VERSION 5.7 ;
  NOWIREEXTENSIONATPIN ON ;
  DIVIDERCHAR "/" ;
  BUSBITCHARS "[]" ;
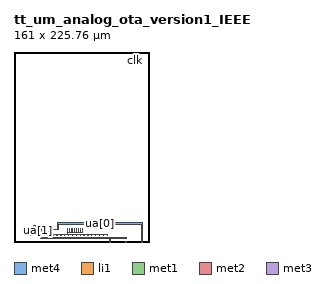
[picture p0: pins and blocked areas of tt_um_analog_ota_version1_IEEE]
MACRO tt_um_analog_ota_version1_IEEE
  CLASS BLOCK ;
  FOREIGN tt_um_analog_ota_version1_IEEE ;
  ORIGIN 0.000 0.000 ;
  SIZE 161.000 BY 225.760 ;
  PIN clk
    PORT
      LAYER met4 ;
        RECT 143.830 224.760 144.130 225.760 ;
    END
  END clk
  PIN ena
    PORT
      LAYER met4 ;
        RECT 146.590 224.760 146.890 225.760 ;
    END
  END ena
  PIN rst_n
    PORT
      LAYER met4 ;
        RECT 141.070 224.760 141.370 225.760 ;
    END
  END rst_n
  PIN ua[0]
    ANTENNAGATEAREA 0.625000 ;
    PORT
      LAYER li1 ;
        RECT 46.745 14.570 47.275 14.740 ;
      LAYER met1 ;
        RECT 49.605 14.800 50.225 14.875 ;
        RECT 46.770 14.510 50.225 14.800 ;
        RECT 49.605 14.395 50.225 14.510 ;
      LAYER met2 ;
        RECT 49.655 14.345 50.175 14.925 ;
      LAYER met3 ;
        RECT 49.605 14.370 50.225 14.900 ;
      LAYER met4 ;
        RECT 149.905 23.100 152.760 23.105 ;
        RECT 51.885 20.845 152.760 23.100 ;
        RECT 51.895 14.895 52.480 20.845 ;
        RECT 151.810 20.790 152.760 20.845 ;
        RECT 50.070 14.880 52.485 14.895 ;
        RECT 49.650 14.390 52.485 14.880 ;
        RECT 50.070 14.365 52.485 14.390 ;
        RECT 151.810 0.320 152.745 20.790 ;
        RECT 151.810 0.000 152.710 0.320 ;
    END
  END ua[0]
  PIN ua[1]
    ANTENNAGATEAREA 0.625000 ;
    ANTENNADIFFAREA 15.500500 ;
    PORT
      LAYER li1 ;
        RECT 45.955 14.570 46.485 14.740 ;
        RECT 63.660 11.000 63.830 16.340 ;
        RECT 66.240 11.000 66.410 16.340 ;
        RECT 68.820 11.000 68.990 16.340 ;
        RECT 71.400 11.000 71.570 16.340 ;
        RECT 73.980 11.000 74.150 16.340 ;
        RECT 76.560 11.000 76.730 16.340 ;
        RECT 79.140 11.000 79.310 16.340 ;
        RECT 81.720 11.000 81.890 16.340 ;
        RECT 20.260 7.885 20.430 8.575 ;
        RECT 41.935 8.270 42.105 8.960 ;
        RECT 46.515 8.270 46.685 8.960 ;
        RECT 51.095 8.270 51.265 8.960 ;
        RECT 55.675 8.270 55.845 8.960 ;
        RECT 60.255 8.270 60.425 8.960 ;
        RECT 64.835 8.270 65.005 8.960 ;
        RECT 69.415 8.270 69.585 8.960 ;
        RECT 73.995 8.270 74.165 8.960 ;
        RECT 78.575 8.270 78.745 8.960 ;
        RECT 83.155 8.270 83.325 8.960 ;
        RECT 87.735 8.270 87.905 8.960 ;
        RECT 92.315 8.270 92.485 8.960 ;
        RECT 96.895 8.270 97.065 8.960 ;
        RECT 101.475 8.270 101.645 8.960 ;
        RECT 106.055 8.270 106.225 8.960 ;
        RECT 110.635 8.270 110.805 8.960 ;
      LAYER met1 ;
        RECT 42.955 14.795 43.595 14.950 ;
        RECT 45.980 14.795 46.460 14.800 ;
        RECT 42.955 14.510 46.460 14.795 ;
        RECT 42.955 14.400 43.595 14.510 ;
        RECT 63.630 11.340 63.860 16.320 ;
        RECT 66.210 11.340 66.440 16.320 ;
        RECT 68.790 11.340 69.020 16.320 ;
        RECT 71.370 11.340 71.600 16.320 ;
        RECT 73.950 11.340 74.180 16.320 ;
        RECT 76.530 11.340 76.760 16.320 ;
        RECT 79.110 11.340 79.340 16.320 ;
        RECT 81.690 11.340 81.920 16.320 ;
        RECT 63.615 11.020 63.875 11.340 ;
        RECT 66.195 11.020 66.455 11.340 ;
        RECT 68.775 11.020 69.035 11.340 ;
        RECT 71.355 11.020 71.615 11.340 ;
        RECT 73.935 11.020 74.195 11.340 ;
        RECT 76.515 11.020 76.775 11.340 ;
        RECT 79.095 11.020 79.355 11.340 ;
        RECT 81.675 11.020 81.935 11.340 ;
        RECT 41.900 8.615 42.160 8.960 ;
        RECT 46.480 8.615 46.740 8.960 ;
        RECT 51.060 8.615 51.320 8.960 ;
        RECT 55.640 8.615 55.900 8.960 ;
        RECT 60.220 8.615 60.480 8.960 ;
        RECT 64.800 8.615 65.060 8.960 ;
        RECT 69.380 8.615 69.640 8.960 ;
        RECT 73.960 8.615 74.220 8.960 ;
        RECT 78.540 8.615 78.800 8.960 ;
        RECT 83.120 8.615 83.380 8.960 ;
        RECT 87.700 8.615 87.960 8.960 ;
        RECT 92.280 8.615 92.540 8.960 ;
        RECT 96.860 8.615 97.120 8.960 ;
        RECT 101.440 8.615 101.700 8.960 ;
        RECT 106.020 8.615 106.280 8.960 ;
        RECT 110.600 8.615 110.860 8.960 ;
        RECT 20.260 8.555 20.430 8.575 ;
        RECT 20.225 8.510 20.460 8.555 ;
        RECT 20.170 8.245 20.535 8.510 ;
        RECT 41.905 8.290 42.135 8.615 ;
        RECT 46.485 8.290 46.715 8.615 ;
        RECT 51.065 8.290 51.295 8.615 ;
        RECT 55.645 8.290 55.875 8.615 ;
        RECT 60.225 8.290 60.455 8.615 ;
        RECT 64.805 8.290 65.035 8.615 ;
        RECT 69.385 8.290 69.615 8.615 ;
        RECT 73.965 8.290 74.195 8.615 ;
        RECT 78.545 8.290 78.775 8.615 ;
        RECT 83.125 8.290 83.355 8.615 ;
        RECT 87.705 8.290 87.935 8.615 ;
        RECT 92.285 8.290 92.515 8.615 ;
        RECT 96.865 8.290 97.095 8.615 ;
        RECT 101.445 8.290 101.675 8.615 ;
        RECT 106.025 8.290 106.255 8.615 ;
        RECT 110.605 8.290 110.835 8.615 ;
        RECT 20.225 7.905 20.460 8.245 ;
      LAYER met2 ;
        RECT 43.005 14.350 43.545 15.000 ;
        RECT 38.480 12.890 42.165 12.900 ;
        RECT 38.215 12.510 42.165 12.890 ;
        RECT 38.480 12.500 42.165 12.510 ;
        RECT 41.895 11.790 42.165 12.500 ;
        RECT 41.900 8.930 42.165 11.790 ;
        RECT 63.585 11.265 63.905 11.310 ;
        RECT 66.165 11.265 66.485 11.310 ;
        RECT 68.745 11.265 69.065 11.310 ;
        RECT 71.325 11.265 71.645 11.310 ;
        RECT 73.905 11.265 74.225 11.310 ;
        RECT 76.485 11.265 76.805 11.310 ;
        RECT 79.065 11.265 79.385 11.310 ;
        RECT 81.645 11.265 81.965 11.310 ;
        RECT 63.585 11.065 81.965 11.265 ;
        RECT 63.585 11.050 63.905 11.065 ;
        RECT 66.165 11.050 66.485 11.065 ;
        RECT 68.745 11.050 69.065 11.065 ;
        RECT 71.325 11.050 71.645 11.065 ;
        RECT 73.905 11.050 74.225 11.065 ;
        RECT 76.485 11.050 76.805 11.065 ;
        RECT 79.065 11.050 79.385 11.065 ;
        RECT 81.645 11.050 81.965 11.065 ;
        RECT 41.850 8.885 42.210 8.930 ;
        RECT 46.430 8.885 46.790 8.930 ;
        RECT 51.010 8.885 51.370 8.930 ;
        RECT 55.590 8.885 55.950 8.930 ;
        RECT 60.170 8.885 60.530 8.930 ;
        RECT 63.615 8.885 63.875 11.050 ;
        RECT 64.750 8.885 65.110 8.930 ;
        RECT 69.330 8.885 69.690 8.930 ;
        RECT 73.910 8.885 74.270 8.930 ;
        RECT 78.490 8.885 78.850 8.930 ;
        RECT 83.070 8.885 83.430 8.930 ;
        RECT 87.650 8.885 88.010 8.930 ;
        RECT 92.230 8.885 92.590 8.930 ;
        RECT 96.810 8.885 97.170 8.930 ;
        RECT 101.390 8.885 101.750 8.930 ;
        RECT 105.970 8.885 106.330 8.930 ;
        RECT 110.550 8.885 110.910 8.930 ;
        RECT 41.850 8.735 110.910 8.885 ;
        RECT 41.850 8.665 42.210 8.735 ;
        RECT 46.430 8.665 46.790 8.735 ;
        RECT 51.010 8.665 51.370 8.735 ;
        RECT 55.590 8.665 55.950 8.735 ;
        RECT 60.170 8.665 60.530 8.735 ;
        RECT 64.750 8.665 65.110 8.735 ;
        RECT 69.330 8.665 69.690 8.735 ;
        RECT 73.910 8.665 74.270 8.735 ;
        RECT 78.490 8.665 78.850 8.735 ;
        RECT 83.070 8.665 83.430 8.735 ;
        RECT 87.650 8.665 88.010 8.735 ;
        RECT 92.230 8.665 92.590 8.735 ;
        RECT 96.810 8.665 97.170 8.735 ;
        RECT 101.390 8.665 101.750 8.735 ;
        RECT 105.970 8.665 106.330 8.735 ;
        RECT 110.550 8.665 110.910 8.735 ;
        RECT 20.205 8.185 20.490 8.560 ;
      LAYER met3 ;
        RECT 22.650 8.900 35.360 19.350 ;
        RECT 42.955 14.375 43.595 14.975 ;
        RECT 38.100 12.450 38.700 12.950 ;
        RECT 21.230 8.550 35.360 8.900 ;
        RECT 20.175 8.530 20.515 8.540 ;
        RECT 21.230 8.530 21.600 8.550 ;
        RECT 20.070 8.230 21.600 8.530 ;
        RECT 22.650 8.400 35.360 8.550 ;
        RECT 20.175 8.205 20.515 8.230 ;
        RECT 21.230 8.225 21.600 8.230 ;
      LAYER met4 ;
        RECT 23.045 12.865 33.205 18.955 ;
        RECT 34.860 12.865 35.340 19.290 ;
        RECT 43.000 14.585 43.550 14.955 ;
        RECT 23.045 12.535 38.565 12.865 ;
        RECT 23.045 12.525 38.260 12.535 ;
        RECT 23.045 8.795 33.205 12.525 ;
        RECT 31.145 5.350 32.650 8.795 ;
        RECT 34.860 8.460 35.340 12.525 ;
        RECT 42.955 5.400 43.620 14.585 ;
        RECT 42.955 5.350 133.425 5.400 ;
        RECT 31.145 4.150 133.425 5.350 ;
        RECT 31.145 4.125 45.100 4.150 ;
<<<<<<< HEAD
        RECT 93.850 0.000 94.750 4.150 ;
        RECT 113.170 0.000 114.070 4.150 ;
=======
>>>>>>> 167fef3d94abc1b400a22c40856cbbf2e635c482
        RECT 132.470 0.715 133.405 4.150 ;
        RECT 132.490 0.000 133.390 0.715 ;
    END
  END ua[1]
<<<<<<< HEAD
=======
  PIN ua[2]
    PORT
      LAYER met4 ;
        RECT 113.170 0.000 114.070 1.000 ;
    END
  END ua[2]
  PIN ua[3]
    PORT
      LAYER met4 ;
        RECT 93.850 0.000 94.750 1.000 ;
    END
  END ua[3]
>>>>>>> 167fef3d94abc1b400a22c40856cbbf2e635c482
  PIN ua[4]
    PORT
      LAYER met4 ;
        RECT 74.530 0.000 75.430 1.000 ;
    END
  END ua[4]
  PIN ua[5]
    PORT
      LAYER met4 ;
        RECT 55.210 0.000 56.110 1.000 ;
    END
  END ua[5]
  PIN ua[6]
    PORT
      LAYER met4 ;
        RECT 35.890 0.000 36.790 1.000 ;
    END
  END ua[6]
  PIN ua[7]
    PORT
      LAYER met4 ;
        RECT 16.570 0.000 17.470 1.000 ;
    END
  END ua[7]
  PIN ui_in[0]
    PORT
      LAYER met4 ;
        RECT 138.310 224.760 138.610 225.760 ;
    END
  END ui_in[0]
  PIN ui_in[1]
    PORT
      LAYER met4 ;
        RECT 135.550 224.760 135.850 225.760 ;
    END
  END ui_in[1]
  PIN ui_in[2]
    PORT
      LAYER met4 ;
        RECT 132.790 224.760 133.090 225.760 ;
    END
  END ui_in[2]
  PIN ui_in[3]
    PORT
      LAYER met4 ;
        RECT 130.030 224.760 130.330 225.760 ;
    END
  END ui_in[3]
  PIN ui_in[4]
    PORT
      LAYER met4 ;
        RECT 127.270 224.760 127.570 225.760 ;
    END
  END ui_in[4]
  PIN ui_in[5]
    PORT
      LAYER met4 ;
        RECT 124.510 224.760 124.810 225.760 ;
    END
  END ui_in[5]
  PIN ui_in[6]
    PORT
      LAYER met4 ;
        RECT 121.750 224.760 122.050 225.760 ;
    END
  END ui_in[6]
  PIN ui_in[7]
    PORT
      LAYER met4 ;
        RECT 118.990 224.760 119.290 225.760 ;
    END
  END ui_in[7]
  PIN uio_in[0]
    PORT
      LAYER met4 ;
        RECT 116.230 224.760 116.530 225.760 ;
    END
  END uio_in[0]
  PIN uio_in[1]
    PORT
      LAYER met4 ;
        RECT 113.470 224.760 113.770 225.760 ;
    END
  END uio_in[1]
  PIN uio_in[2]
    PORT
      LAYER met4 ;
        RECT 110.710 224.760 111.010 225.760 ;
    END
  END uio_in[2]
  PIN uio_in[3]
    PORT
      LAYER met4 ;
        RECT 107.950 224.760 108.250 225.760 ;
    END
  END uio_in[3]
  PIN uio_in[4]
    PORT
      LAYER met4 ;
        RECT 105.190 224.760 105.490 225.760 ;
    END
  END uio_in[4]
  PIN uio_in[5]
    PORT
      LAYER met4 ;
        RECT 102.430 224.760 102.730 225.760 ;
    END
  END uio_in[5]
  PIN uio_in[6]
    PORT
      LAYER met4 ;
        RECT 99.670 224.760 99.970 225.760 ;
    END
  END uio_in[6]
  PIN uio_in[7]
    PORT
      LAYER met4 ;
        RECT 96.910 224.760 97.210 225.760 ;
    END
  END uio_in[7]
  PIN uio_oe[0]
    PORT
      LAYER met4 ;
        RECT 49.990 224.760 50.290 225.760 ;
    END
  END uio_oe[0]
  PIN uio_oe[1]
    PORT
      LAYER met4 ;
        RECT 47.230 224.760 47.530 225.760 ;
    END
  END uio_oe[1]
  PIN uio_oe[2]
    PORT
      LAYER met4 ;
        RECT 44.470 224.760 44.770 225.760 ;
    END
  END uio_oe[2]
  PIN uio_oe[3]
    PORT
      LAYER met4 ;
        RECT 41.710 224.760 42.010 225.760 ;
    END
  END uio_oe[3]
  PIN uio_oe[4]
    PORT
      LAYER met4 ;
        RECT 38.950 224.760 39.250 225.760 ;
    END
  END uio_oe[4]
  PIN uio_oe[5]
    PORT
      LAYER met4 ;
        RECT 36.190 224.760 36.490 225.760 ;
    END
  END uio_oe[5]
  PIN uio_oe[6]
    PORT
      LAYER met4 ;
        RECT 33.430 224.760 33.730 225.760 ;
    END
  END uio_oe[6]
  PIN uio_oe[7]
    PORT
      LAYER met4 ;
        RECT 30.670 224.760 30.970 225.760 ;
    END
  END uio_oe[7]
  PIN uio_out[0]
    PORT
      LAYER met4 ;
        RECT 72.070 224.760 72.370 225.760 ;
    END
  END uio_out[0]
  PIN uio_out[1]
    PORT
      LAYER met4 ;
        RECT 69.310 224.760 69.610 225.760 ;
    END
  END uio_out[1]
  PIN uio_out[2]
    PORT
      LAYER met4 ;
        RECT 66.550 224.760 66.850 225.760 ;
    END
  END uio_out[2]
  PIN uio_out[3]
    PORT
      LAYER met4 ;
        RECT 63.790 224.760 64.090 225.760 ;
    END
  END uio_out[3]
  PIN uio_out[4]
    PORT
      LAYER met4 ;
        RECT 61.030 224.760 61.330 225.760 ;
    END
  END uio_out[4]
  PIN uio_out[5]
    PORT
      LAYER met4 ;
        RECT 58.270 224.760 58.570 225.760 ;
    END
  END uio_out[5]
  PIN uio_out[6]
    PORT
      LAYER met4 ;
        RECT 55.510 224.760 55.810 225.760 ;
    END
  END uio_out[6]
  PIN uio_out[7]
    PORT
      LAYER met4 ;
        RECT 52.750 224.760 53.050 225.760 ;
    END
  END uio_out[7]
  PIN uo_out[0]
    PORT
      LAYER met4 ;
        RECT 94.150 224.760 94.450 225.760 ;
    END
  END uo_out[0]
  PIN uo_out[1]
    PORT
      LAYER met4 ;
        RECT 91.390 224.760 91.690 225.760 ;
    END
  END uo_out[1]
  PIN uo_out[2]
    PORT
      LAYER met4 ;
        RECT 88.630 224.760 88.930 225.760 ;
    END
  END uo_out[2]
  PIN uo_out[3]
    PORT
      LAYER met4 ;
        RECT 85.870 224.760 86.170 225.760 ;
    END
  END uo_out[3]
  PIN uo_out[4]
    PORT
      LAYER met4 ;
        RECT 83.110 224.760 83.410 225.760 ;
    END
  END uo_out[4]
  PIN uo_out[5]
    PORT
      LAYER met4 ;
        RECT 80.350 224.760 80.650 225.760 ;
    END
  END uo_out[5]
  PIN uo_out[6]
    PORT
      LAYER met4 ;
        RECT 77.590 224.760 77.890 225.760 ;
    END
  END uo_out[6]
  PIN uo_out[7]
    PORT
      LAYER met4 ;
        RECT 74.830 224.760 75.130 225.760 ;
    END
  END uo_out[7]
  PIN VDPWR
    ANTENNAGATEAREA 51.799999 ;
    ANTENNADIFFAREA 81.053673 ;
    PORT
      LAYER nwell ;
        RECT 25.420 35.070 36.370 36.105 ;
        RECT 25.430 33.945 36.370 35.070 ;
        RECT 37.640 34.625 45.770 46.605 ;
        RECT 15.765 12.110 22.545 19.340 ;
        RECT 43.215 16.660 49.995 23.890 ;
        RECT 59.635 9.915 84.715 17.395 ;
      LAYER li1 ;
        RECT 37.820 46.255 45.590 46.425 ;
        RECT 25.965 35.305 35.805 35.860 ;
        RECT 37.820 34.975 37.990 46.255 ;
        RECT 38.455 35.685 38.625 45.725 ;
        RECT 39.745 35.685 39.915 45.725 ;
        RECT 41.625 35.685 41.795 45.725 ;
        RECT 43.505 35.685 43.675 45.725 ;
        RECT 44.795 35.685 44.965 45.725 ;
        RECT 38.685 35.300 39.685 35.470 ;
        RECT 43.735 35.300 44.735 35.470 ;
        RECT 45.420 34.975 45.590 46.255 ;
        RECT 35.960 34.425 36.130 34.965 ;
        RECT 37.820 34.805 45.590 34.975 ;
        RECT 43.395 23.540 49.815 23.710 ;
        RECT 15.945 18.990 22.365 19.160 ;
        RECT 15.945 12.460 16.115 18.990 ;
        RECT 16.800 18.520 17.800 18.690 ;
        RECT 20.500 18.520 21.500 18.690 ;
        RECT 16.570 12.965 16.740 18.305 ;
        RECT 17.860 12.965 18.030 18.305 ;
        RECT 19.710 12.965 19.880 18.305 ;
        RECT 20.270 12.965 20.440 18.305 ;
        RECT 21.560 12.965 21.730 18.305 ;
        RECT 22.195 12.460 22.365 18.990 ;
        RECT 43.395 17.010 43.565 23.540 ;
        RECT 44.250 23.070 45.250 23.240 ;
        RECT 47.950 23.070 48.950 23.240 ;
        RECT 44.020 17.515 44.190 22.855 ;
        RECT 45.310 17.515 45.480 22.855 ;
        RECT 47.160 17.515 47.330 22.855 ;
        RECT 47.720 17.515 47.890 22.855 ;
        RECT 49.010 17.515 49.180 22.855 ;
        RECT 49.645 17.010 49.815 23.540 ;
        RECT 43.395 16.840 49.815 17.010 ;
        RECT 59.815 17.045 84.535 17.215 ;
        RECT 15.945 12.290 22.365 12.460 ;
        RECT 59.815 10.265 59.985 17.045 ;
        RECT 60.750 16.555 61.750 16.725 ;
        RECT 82.550 16.555 83.550 16.725 ;
        RECT 60.520 11.000 60.690 16.340 ;
        RECT 61.810 11.000 61.980 16.340 ;
        RECT 62.370 11.000 62.540 16.340 ;
        RECT 64.950 11.000 65.120 16.340 ;
        RECT 67.530 11.000 67.700 16.340 ;
        RECT 70.110 11.000 70.280 16.340 ;
        RECT 72.690 11.000 72.860 16.340 ;
        RECT 75.270 11.000 75.440 16.340 ;
        RECT 77.850 11.000 78.020 16.340 ;
        RECT 80.430 11.000 80.600 16.340 ;
        RECT 82.320 11.000 82.490 16.340 ;
        RECT 83.610 11.000 83.780 16.340 ;
        RECT 60.750 10.615 61.750 10.785 ;
        RECT 82.550 10.615 83.550 10.785 ;
        RECT 84.365 10.265 84.535 17.045 ;
        RECT 59.815 10.095 84.535 10.265 ;
      LAYER met1 ;
        RECT 38.060 46.225 45.350 46.455 ;
        RECT 37.790 40.400 38.020 40.705 ;
        RECT 33.995 40.365 38.020 40.400 ;
        RECT 32.890 39.100 38.020 40.365 ;
        RECT 32.890 39.095 34.020 39.100 ;
        RECT 32.940 35.870 33.955 39.095 ;
        RECT 37.790 38.815 38.020 39.100 ;
        RECT 25.930 35.290 36.160 35.870 ;
        RECT 38.425 35.500 38.655 45.705 ;
        RECT 39.715 35.500 39.945 45.705 ;
        RECT 41.595 35.705 41.825 46.225 ;
        RECT 38.425 35.375 39.945 35.500 ;
        RECT 43.475 35.500 43.705 45.705 ;
        RECT 44.765 35.500 44.995 45.705 ;
        RECT 43.475 35.375 44.995 35.500 ;
        RECT 35.930 34.445 36.160 35.290 ;
        RECT 38.420 35.005 39.945 35.375 ;
        RECT 43.470 35.005 44.995 35.375 ;
        RECT 38.060 34.775 45.350 35.005 ;
        RECT 45.565 26.395 46.905 27.055 ;
        RECT 45.560 26.130 46.905 26.395 ;
        RECT 45.560 23.740 46.900 26.130 ;
        RECT 43.635 23.510 49.575 23.740 ;
        RECT 43.990 23.270 44.255 23.510 ;
        RECT 48.945 23.270 49.210 23.510 ;
        RECT 43.990 23.040 45.510 23.270 ;
        RECT 47.870 23.265 49.210 23.270 ;
        RECT 43.990 22.835 44.215 23.040 ;
        RECT 16.185 18.960 22.125 19.190 ;
        RECT 16.540 18.720 16.805 18.960 ;
        RECT 21.495 18.720 21.760 18.960 ;
        RECT 16.540 18.490 18.060 18.720 ;
        RECT 20.420 18.715 21.760 18.720 ;
        RECT 16.540 18.285 16.765 18.490 ;
        RECT 15.915 15.230 16.145 15.285 ;
        RECT 10.195 13.975 16.145 15.230 ;
        RECT 11.520 13.970 16.145 13.975 ;
        RECT 15.915 13.905 16.145 13.970 ;
        RECT 16.540 12.985 16.770 18.285 ;
        RECT 17.830 12.985 18.060 18.490 ;
        RECT 20.240 18.490 21.760 18.715 ;
        RECT 19.680 12.490 19.910 18.285 ;
        RECT 20.240 12.985 20.470 18.490 ;
        RECT 21.530 12.985 21.760 18.490 ;
        RECT 43.990 17.535 44.220 22.835 ;
        RECT 45.280 17.535 45.510 23.040 ;
        RECT 47.690 23.040 49.210 23.265 ;
        RECT 47.130 17.040 47.360 22.835 ;
        RECT 47.690 17.535 47.920 23.040 ;
        RECT 48.980 17.535 49.210 23.040 ;
        RECT 65.175 17.245 67.425 20.380 ;
        RECT 43.635 16.810 49.575 17.040 ;
        RECT 65.140 17.015 67.485 17.245 ;
        RECT 59.785 16.755 60.015 16.860 ;
        RECT 84.335 16.765 84.565 16.910 ;
        RECT 83.805 16.760 84.565 16.765 ;
        RECT 83.490 16.755 84.565 16.760 ;
        RECT 59.785 16.525 62.010 16.755 ;
        RECT 59.785 16.320 60.720 16.525 ;
        RECT 59.785 16.200 60.015 16.320 ;
        RECT 16.185 12.260 22.125 12.490 ;
        RECT 60.490 11.020 60.720 16.320 ;
        RECT 61.780 16.350 62.010 16.525 ;
        RECT 82.290 16.525 84.565 16.755 ;
        RECT 61.780 16.030 62.585 16.350 ;
        RECT 64.905 16.030 65.165 16.350 ;
        RECT 67.485 16.030 67.745 16.350 ;
        RECT 70.065 16.030 70.325 16.350 ;
        RECT 72.645 16.030 72.905 16.350 ;
        RECT 75.225 16.030 75.485 16.350 ;
        RECT 77.805 16.030 78.065 16.350 ;
        RECT 80.385 16.030 80.645 16.350 ;
        RECT 61.780 15.650 62.570 16.030 ;
        RECT 61.780 11.020 62.010 15.650 ;
        RECT 62.340 11.020 62.570 15.650 ;
        RECT 64.920 11.020 65.150 16.030 ;
        RECT 67.500 11.020 67.730 16.030 ;
        RECT 70.080 11.020 70.310 16.030 ;
        RECT 72.660 11.020 72.890 16.030 ;
        RECT 75.240 11.020 75.470 16.030 ;
        RECT 77.820 11.020 78.050 16.030 ;
        RECT 80.400 11.020 80.630 16.030 ;
        RECT 82.290 11.020 82.520 16.525 ;
        RECT 83.490 16.520 84.565 16.525 ;
        RECT 83.580 16.515 84.565 16.520 ;
        RECT 83.580 11.020 83.810 16.515 ;
        RECT 84.335 15.960 84.565 16.515 ;
        RECT 60.770 10.585 61.730 10.815 ;
        RECT 82.570 10.585 83.530 10.815 ;
      LAYER met2 ;
        RECT 32.940 39.045 33.970 40.415 ;
        RECT 45.615 26.080 46.855 27.105 ;
        RECT 65.455 18.965 67.085 20.415 ;
        RECT 62.295 16.260 62.615 16.320 ;
        RECT 64.875 16.260 65.195 16.320 ;
        RECT 67.455 16.260 67.775 16.320 ;
        RECT 70.035 16.260 70.355 16.320 ;
        RECT 72.615 16.260 72.935 16.320 ;
        RECT 75.195 16.260 75.515 16.320 ;
        RECT 77.775 16.260 78.095 16.320 ;
        RECT 80.355 16.260 80.675 16.320 ;
        RECT 62.295 16.060 80.675 16.260 ;
        RECT 10.230 13.920 11.500 15.285 ;
      LAYER met3 ;
        RECT 1.110 40.745 2.645 40.890 ;
        RECT 1.110 38.795 34.415 40.745 ;
        RECT 1.305 27.600 67.310 27.655 ;
        RECT 1.305 27.095 67.415 27.600 ;
        RECT 1.255 25.755 67.415 27.095 ;
        RECT 65.175 18.650 67.415 25.755 ;
        RECT 1.280 15.420 11.755 15.440 ;
        RECT 1.230 13.735 11.755 15.420 ;
      LAYER met4 ;
        RECT 1.000 5.000 3.000 220.760 ;
    END
  END VDPWR
  PIN VGND
    USE GROUND ;
    PORT
      LAYER pwell ;
<<<<<<< HEAD
        RECT 22.620 35.765 25.370 36.195 ;
        RECT 22.620 32.740 23.050 35.765 ;
        RECT 24.940 33.825 25.370 35.765 ;
        RECT 43.670 34.525 46.500 34.625 ;
        RECT 36.920 34.195 46.500 34.525 ;
        RECT 36.920 34.095 44.100 34.195 ;
        RECT 24.940 33.395 27.970 33.825 ;
        RECT 24.940 32.740 26.465 33.395 ;
        RECT 22.620 32.310 26.465 32.740 ;
        RECT 26.035 31.425 26.465 32.310 ;
        RECT 27.540 31.425 27.970 33.395 ;
        RECT 26.035 30.995 27.970 31.425 ;
        RECT 36.920 28.075 37.350 34.095 ;
        RECT 43.220 28.075 44.100 34.095 ;
        RECT 46.070 28.075 46.500 34.195 ;
        RECT 36.920 27.645 46.500 28.075 ;
        RECT 37.095 27.205 40.065 27.635 ;
        RECT 37.095 16.895 37.525 27.205 ;
        RECT 39.635 16.895 40.065 27.205 ;
        RECT 37.095 16.465 40.065 16.895 ;
        RECT 16.070 11.645 22.250 12.075 ;
        RECT 16.070 11.270 17.080 11.645 ;
        RECT 18.935 11.270 19.365 11.645 ;
        RECT 21.230 11.270 22.250 11.645 ;
        RECT 16.070 10.360 22.250 11.270 ;
        RECT 16.070 9.975 17.080 10.360 ;
        RECT 18.935 9.975 19.365 10.360 ;
        RECT 21.230 9.975 22.250 10.360 ;
        RECT 16.070 9.545 22.250 9.975 ;
        RECT 43.580 11.815 49.760 12.245 ;
        RECT 43.580 11.390 44.585 11.815 ;
        RECT 46.445 11.390 46.875 11.815 ;
        RECT 48.740 11.390 49.760 11.815 ;
        RECT 43.580 10.480 49.760 11.390 ;
        RECT 43.580 10.395 44.585 10.480 ;
        RECT 46.445 10.395 46.875 10.480 ;
        RECT 48.740 10.395 49.760 10.480 ;
        RECT 43.580 9.915 49.760 10.395 ;
        RECT 17.265 9.060 21.145 9.545 ;
        RECT 17.265 8.685 18.270 9.060 ;
        RECT 20.130 8.685 21.145 9.060 ;
        RECT 17.265 7.775 21.145 8.685 ;
        RECT 17.265 7.690 18.270 7.775 ;
        RECT 20.130 7.690 21.145 7.775 ;
        RECT 17.265 7.260 21.145 7.690 ;
        RECT 38.410 9.485 114.440 9.915 ;
        RECT 38.410 7.715 38.840 9.485 ;
        RECT 114.010 7.715 114.440 9.485 ;
        RECT 38.410 7.285 114.440 7.715 ;
=======
        RECT 37.045 16.415 40.115 27.685 ;
>>>>>>> 167fef3d94abc1b400a22c40856cbbf2e635c482
      LAYER li1 ;
        RECT 22.750 35.895 25.240 36.065 ;
        RECT 22.750 32.610 22.920 35.895 ;
        RECT 25.070 32.610 25.240 35.895 ;
        RECT 37.050 34.225 43.520 34.395 ;
        RECT 22.750 32.440 25.240 32.610 ;
        RECT 26.165 33.525 27.840 33.695 ;
        RECT 26.165 31.295 26.335 33.525 ;
        RECT 27.140 31.885 27.310 32.925 ;
        RECT 27.670 31.295 27.840 33.525 ;
        RECT 26.165 31.125 27.840 31.295 ;
        RECT 37.050 30.215 37.220 34.225 ;
        RECT 37.050 29.005 37.225 30.215 ;
        RECT 37.050 27.945 37.220 29.005 ;
        RECT 43.350 27.945 43.520 34.225 ;
        RECT 37.050 27.775 43.520 27.945 ;
        RECT 43.800 34.325 46.370 34.495 ;
        RECT 43.800 27.945 43.970 34.325 ;
        RECT 45.655 28.630 45.825 33.670 ;
        RECT 46.200 27.945 46.370 34.325 ;
        RECT 43.800 27.775 46.370 27.945 ;
        RECT 37.225 27.335 39.935 27.505 ;
        RECT 37.225 16.765 37.395 27.335 ;
        RECT 37.875 17.245 39.285 19.405 ;
        RECT 39.765 16.765 39.935 27.335 ;
        RECT 37.225 16.595 39.935 16.765 ;
        RECT 43.710 11.945 49.630 12.115 ;
        RECT 16.200 11.775 22.120 11.945 ;
        RECT 16.200 11.315 16.370 11.775 ;
        RECT 16.195 10.080 16.370 11.315 ;
        RECT 21.360 10.470 21.530 11.160 ;
        RECT 16.200 9.845 16.370 10.080 ;
        RECT 21.950 9.845 22.120 11.775 ;
        RECT 43.710 10.265 43.880 11.945 ;
        RECT 46.575 10.590 46.745 11.280 ;
        RECT 49.460 10.265 49.630 11.945 ;
        RECT 43.710 10.095 49.630 10.265 ;
        RECT 16.200 9.675 22.120 9.845 ;
        RECT 38.540 9.615 114.310 9.785 ;
        RECT 17.395 9.190 21.015 9.360 ;
        RECT 17.395 7.560 17.565 9.190 ;
        RECT 20.845 7.560 21.015 9.190 ;
        RECT 17.395 7.390 21.015 7.560 ;
        RECT 38.540 7.585 38.710 9.615 ;
        RECT 39.315 9.130 41.315 9.300 ;
        RECT 111.515 9.130 113.515 9.300 ;
        RECT 39.085 8.270 39.255 8.960 ;
        RECT 41.375 8.270 41.545 8.960 ;
        RECT 44.225 8.270 44.395 8.960 ;
        RECT 48.805 8.270 48.975 8.960 ;
        RECT 53.385 8.270 53.555 8.960 ;
        RECT 57.965 8.270 58.135 8.960 ;
        RECT 62.545 8.270 62.715 8.960 ;
        RECT 67.125 8.270 67.295 8.960 ;
        RECT 71.705 8.270 71.875 8.960 ;
        RECT 76.285 8.270 76.455 8.960 ;
        RECT 80.865 8.270 81.035 8.960 ;
        RECT 85.445 8.270 85.615 8.960 ;
        RECT 90.025 8.270 90.195 8.960 ;
        RECT 94.605 8.270 94.775 8.960 ;
        RECT 99.185 8.270 99.355 8.960 ;
        RECT 103.765 8.270 103.935 8.960 ;
        RECT 108.345 8.270 108.515 8.960 ;
        RECT 111.285 8.270 111.455 8.960 ;
        RECT 113.575 8.270 113.745 8.960 ;
        RECT 39.315 7.930 41.315 8.100 ;
        RECT 111.515 7.930 113.515 8.100 ;
        RECT 114.140 7.585 114.310 9.615 ;
        RECT 38.540 7.415 114.310 7.585 ;
      LAYER met1 ;
        RECT 46.170 33.650 46.400 34.135 ;
        RECT 27.640 32.910 27.870 32.965 ;
        RECT 27.640 32.905 33.760 32.910 ;
        RECT 24.190 30.430 24.585 32.640 ;
        RECT 27.110 31.905 33.760 32.905 ;
        RECT 27.300 31.900 27.870 31.905 ;
        RECT 27.640 31.845 27.870 31.900 ;
        RECT 32.350 30.430 33.760 31.905 ;
        RECT 43.320 31.620 43.910 31.625 ;
        RECT 43.320 30.665 44.000 31.620 ;
        RECT 43.415 30.660 44.000 30.665 ;
        RECT 24.190 30.295 33.760 30.430 ;
        RECT 24.190 30.280 33.870 30.295 ;
        RECT 24.190 30.275 37.105 30.280 ;
        RECT 24.190 30.155 37.255 30.275 ;
        RECT 32.350 29.625 37.255 30.155 ;
        RECT 32.355 29.080 37.255 29.625 ;
        RECT 33.840 29.065 37.255 29.080 ;
        RECT 37.020 28.945 37.255 29.065 ;
        RECT 45.625 28.650 46.400 33.650 ;
        RECT 46.170 28.115 46.400 28.650 ;
        RECT 37.895 16.805 39.265 19.380 ;
        RECT 37.890 16.565 39.265 16.805 ;
        RECT 37.890 15.135 39.260 16.565 ;
        RECT 37.880 13.895 39.340 15.135 ;
        RECT 49.430 12.120 49.660 12.175 ;
        RECT 56.085 12.120 57.320 12.485 ;
        RECT 16.165 11.365 16.400 11.375 ;
        RECT 10.515 10.020 16.400 11.365 ;
        RECT 21.360 11.140 21.530 11.160 ;
        RECT 21.920 11.140 22.150 11.705 ;
        RECT 49.430 11.515 57.320 12.120 ;
        RECT 46.575 11.260 46.745 11.280 ;
        RECT 21.325 10.490 22.150 11.140 ;
        RECT 10.515 9.955 16.230 10.020 ;
        RECT 10.515 9.750 11.550 9.955 ;
        RECT 21.920 9.915 22.150 10.490 ;
        RECT 46.540 10.295 46.775 11.260 ;
        RECT 49.430 10.910 57.315 11.515 ;
        RECT 49.430 10.855 49.660 10.910 ;
        RECT 43.950 10.065 49.390 10.295 ;
        RECT 56.085 9.815 57.315 10.910 ;
        RECT 10.510 9.410 11.575 9.750 ;
        RECT 38.780 9.585 114.070 9.815 ;
        RECT 10.510 8.235 11.605 9.410 ;
        RECT 39.335 9.330 41.295 9.585 ;
        RECT 111.535 9.350 113.495 9.585 ;
        RECT 111.535 9.335 113.775 9.350 ;
        RECT 39.055 9.100 41.575 9.330 ;
        RECT 39.055 8.290 39.285 9.100 ;
        RECT 41.345 8.290 41.575 9.100 ;
        RECT 111.255 9.100 113.775 9.335 ;
        RECT 111.255 9.080 111.485 9.100 ;
        RECT 44.195 8.615 44.425 8.940 ;
        RECT 48.775 8.615 49.005 8.940 ;
        RECT 53.355 8.615 53.585 8.940 ;
        RECT 57.935 8.615 58.165 8.940 ;
        RECT 62.515 8.615 62.745 8.940 ;
        RECT 67.095 8.615 67.325 8.940 ;
        RECT 71.675 8.615 71.905 8.940 ;
        RECT 76.255 8.615 76.485 8.940 ;
        RECT 80.835 8.615 81.065 8.940 ;
        RECT 85.415 8.615 85.645 8.940 ;
        RECT 89.995 8.615 90.225 8.940 ;
        RECT 94.575 8.615 94.805 8.940 ;
        RECT 99.155 8.615 99.385 8.940 ;
        RECT 103.735 8.615 103.965 8.940 ;
        RECT 108.315 8.615 108.545 8.940 ;
        RECT 111.250 8.840 111.485 9.080 ;
        RECT 44.190 8.270 44.450 8.615 ;
        RECT 48.770 8.270 49.030 8.615 ;
        RECT 53.350 8.270 53.610 8.615 ;
        RECT 57.930 8.270 58.190 8.615 ;
        RECT 62.510 8.270 62.770 8.615 ;
        RECT 67.090 8.270 67.350 8.615 ;
        RECT 71.670 8.270 71.930 8.615 ;
        RECT 76.250 8.270 76.510 8.615 ;
        RECT 80.830 8.270 81.090 8.615 ;
        RECT 85.410 8.270 85.670 8.615 ;
        RECT 89.990 8.270 90.250 8.615 ;
        RECT 94.570 8.270 94.830 8.615 ;
        RECT 99.150 8.270 99.410 8.615 ;
        RECT 103.730 8.270 103.990 8.615 ;
        RECT 108.310 8.270 108.570 8.615 ;
        RECT 111.255 8.550 111.485 8.840 ;
        RECT 111.190 8.290 111.550 8.550 ;
        RECT 113.545 8.290 113.775 9.100 ;
        RECT 17.365 8.235 17.595 8.240 ;
        RECT 10.510 7.330 17.595 8.235 ;
        RECT 39.335 7.900 41.295 8.130 ;
        RECT 111.535 7.900 113.495 8.130 ;
        RECT 10.510 7.310 17.475 7.330 ;
      LAYER met2 ;
        RECT 32.405 29.030 33.820 30.345 ;
        RECT 37.930 13.845 39.290 15.185 ;
        RECT 56.135 11.465 57.270 12.535 ;
        RECT 10.560 9.795 11.525 9.800 ;
        RECT 10.550 8.865 11.530 9.795 ;
        RECT 10.560 8.845 11.525 8.865 ;
        RECT 44.140 8.525 44.500 8.585 ;
        RECT 48.720 8.525 49.080 8.585 ;
        RECT 53.300 8.525 53.660 8.585 ;
        RECT 57.880 8.525 58.240 8.585 ;
        RECT 62.460 8.525 62.820 8.585 ;
        RECT 67.040 8.525 67.400 8.585 ;
        RECT 71.620 8.525 71.980 8.585 ;
        RECT 76.200 8.525 76.560 8.585 ;
        RECT 80.780 8.525 81.140 8.585 ;
        RECT 85.360 8.525 85.720 8.585 ;
        RECT 89.940 8.525 90.300 8.585 ;
        RECT 94.520 8.525 94.880 8.585 ;
        RECT 99.100 8.525 99.460 8.585 ;
        RECT 103.680 8.525 104.040 8.585 ;
        RECT 108.260 8.525 108.600 8.585 ;
        RECT 44.140 8.470 108.600 8.525 ;
        RECT 111.240 8.470 111.500 8.600 ;
        RECT 44.140 8.375 111.500 8.470 ;
        RECT 44.140 8.320 44.500 8.375 ;
        RECT 48.720 8.320 49.080 8.375 ;
        RECT 53.300 8.320 53.660 8.375 ;
        RECT 57.880 8.320 58.240 8.375 ;
        RECT 62.460 8.320 62.820 8.375 ;
        RECT 67.040 8.320 67.400 8.375 ;
        RECT 71.620 8.320 71.980 8.375 ;
        RECT 76.200 8.320 76.560 8.375 ;
        RECT 80.780 8.320 81.140 8.375 ;
        RECT 85.360 8.320 85.720 8.375 ;
        RECT 89.940 8.320 90.300 8.375 ;
        RECT 94.520 8.320 94.880 8.375 ;
        RECT 99.100 8.320 99.460 8.375 ;
        RECT 103.680 8.320 104.040 8.375 ;
        RECT 108.260 8.320 111.500 8.375 ;
        RECT 108.280 8.290 111.500 8.320 ;
        RECT 111.240 8.240 111.500 8.290 ;
      LAYER met3 ;
        RECT 4.205 30.550 34.245 30.620 ;
        RECT 4.155 28.890 34.245 30.550 ;
        RECT 4.330 23.775 57.575 24.040 ;
        RECT 4.280 22.845 57.575 23.775 ;
        RECT 4.280 22.375 57.605 22.845 ;
        RECT 37.870 15.470 39.290 15.490 ;
        RECT 40.325 15.470 41.710 22.375 ;
        RECT 55.855 15.490 57.605 22.375 ;
        RECT 37.870 13.875 41.710 15.470 ;
        RECT 37.870 13.865 41.680 13.875 ;
        RECT 55.860 13.865 57.595 15.490 ;
        RECT 55.855 11.210 57.605 13.865 ;
        RECT 4.315 10.030 5.740 10.040 ;
        RECT 4.315 8.625 11.800 10.030 ;
      LAYER met4 ;
        RECT 4.000 5.000 6.000 220.760 ;
    END
  END VGND
  OBS
      LAYER pwell ;
<<<<<<< HEAD
        RECT 23.070 33.165 24.920 35.425 ;
        RECT 26.500 31.775 27.500 33.035 ;
        RECT 37.425 28.470 43.135 33.730 ;
        RECT 44.175 28.520 46.015 33.780 ;
      LAYER nwell ;
        RECT 44.930 12.245 48.310 15.375 ;
      LAYER pwell ;
        RECT 38.895 8.160 41.735 9.070 ;
        RECT 41.745 8.160 110.995 9.070 ;
        RECT 111.095 8.160 113.935 9.070 ;
=======
        RECT 37.425 28.470 43.135 33.730 ;
      LAYER nwell ;
        RECT 44.930 12.245 48.310 15.375 ;
      LAYER pwell ;
        RECT 16.585 10.360 21.715 11.270 ;
        RECT 44.095 10.480 49.225 11.390 ;
        RECT 17.780 7.775 20.620 8.685 ;
        RECT 41.745 8.160 110.995 9.070 ;
>>>>>>> 167fef3d94abc1b400a22c40856cbbf2e635c482
      LAYER li1 ;
        RECT 40.335 35.685 40.505 45.725 ;
        RECT 42.915 35.685 43.085 45.725 ;
        RECT 23.490 35.485 24.490 35.655 ;
        RECT 23.260 33.275 23.430 35.315 ;
        RECT 24.550 33.275 24.720 35.315 ;
        RECT 40.545 35.300 41.585 35.470 ;
        RECT 41.835 35.300 42.875 35.470 ;
        RECT 25.670 34.425 25.840 34.965 ;
        RECT 25.900 34.040 35.900 34.210 ;
        RECT 37.700 33.790 42.860 33.960 ;
        RECT 44.595 33.840 45.595 34.010 ;
        RECT 23.490 32.935 24.490 33.105 ;
<<<<<<< HEAD
        RECT 26.840 33.095 27.170 33.265 ;
=======
>>>>>>> 167fef3d94abc1b400a22c40856cbbf2e635c482
        RECT 26.700 31.885 26.870 32.925 ;
        RECT 26.840 31.545 27.170 31.715 ;
        RECT 37.615 28.580 37.785 33.620 ;
        RECT 38.905 28.580 39.075 33.620 ;
        RECT 40.195 28.580 40.365 33.620 ;
        RECT 41.485 28.580 41.655 33.620 ;
        RECT 42.775 28.580 42.945 33.620 ;
        RECT 44.365 28.630 44.535 33.670 ;
        RECT 37.700 28.240 42.860 28.410 ;
        RECT 44.595 28.290 45.595 28.460 ;
        RECT 37.875 24.695 39.285 26.855 ;
        RECT 46.100 23.070 47.100 23.240 ;
        RECT 18.650 18.520 19.650 18.690 ;
        RECT 18.420 12.965 18.590 18.305 ;
        RECT 45.870 17.515 46.040 22.855 ;
        RECT 62.455 16.555 81.805 16.725 ;
        RECT 45.110 15.025 48.130 15.195 ;
        RECT 45.110 12.595 45.280 15.025 ;
        RECT 45.735 13.065 45.905 14.355 ;
        RECT 46.525 13.065 46.695 14.355 ;
        RECT 47.315 13.065 47.485 14.355 ;
        RECT 47.960 12.595 48.130 15.025 ;
        RECT 45.110 12.425 48.130 12.595 ;
        RECT 16.995 11.330 19.015 11.505 ;
        RECT 44.505 11.450 46.525 11.625 ;
        RECT 46.795 11.450 48.815 11.625 ;
        RECT 16.780 10.470 16.950 11.160 ;
        RECT 19.065 10.470 19.235 11.160 ;
        RECT 44.285 10.590 44.455 11.280 ;
        RECT 48.870 10.590 49.040 11.280 ;
        RECT 62.455 10.615 81.805 10.785 ;
        RECT 19.285 10.125 21.305 10.300 ;
        RECT 42.020 9.130 110.720 9.300 ;
        RECT 18.190 8.745 20.210 8.920 ;
        RECT 17.970 7.885 18.140 8.575 ;
        RECT 42.020 7.930 110.720 8.100 ;
      LAYER met1 ;
        RECT 23.510 35.455 24.470 35.685 ;
        RECT 40.305 35.535 40.535 45.705 ;
        RECT 42.885 35.995 43.115 45.705 ;
        RECT 42.840 35.735 43.160 35.995 ;
        RECT 42.885 35.705 43.115 35.735 ;
        RECT 40.255 35.510 40.575 35.535 ;
        RECT 23.230 33.665 23.460 35.295 ;
        RECT 24.520 33.685 24.750 35.295 ;
        RECT 40.255 35.270 42.855 35.510 ;
        RECT 25.640 34.240 25.870 34.945 ;
        RECT 25.640 34.010 35.880 34.240 ;
        RECT 23.145 33.400 23.515 33.665 ;
        RECT 23.230 33.295 23.460 33.400 ;
        RECT 24.510 33.300 24.785 33.685 ;
        RECT 24.520 33.295 24.750 33.300 ;
        RECT 25.650 33.135 25.855 34.010 ;
        RECT 37.865 33.960 38.825 33.990 ;
        RECT 39.155 33.960 40.115 33.990 ;
        RECT 40.445 33.960 41.405 33.990 ;
        RECT 41.735 33.960 42.695 33.990 ;
        RECT 37.700 33.790 42.860 33.960 ;
        RECT 44.335 33.810 45.575 34.040 ;
        RECT 37.865 33.760 38.825 33.790 ;
        RECT 39.155 33.760 40.115 33.790 ;
        RECT 40.445 33.760 41.405 33.790 ;
        RECT 41.735 33.760 42.695 33.790 ;
        RECT 44.335 33.620 44.565 33.810 ;
<<<<<<< HEAD
        RECT 26.850 33.320 27.210 33.360 ;
        RECT 23.510 32.905 25.855 33.135 ;
        RECT 26.840 33.100 27.210 33.320 ;
        RECT 37.570 33.280 37.830 33.600 ;
        RECT 26.840 33.045 27.170 33.100 ;
=======
        RECT 23.510 32.905 25.855 33.135 ;
        RECT 26.850 33.100 27.210 33.360 ;
        RECT 37.570 33.280 37.830 33.600 ;
>>>>>>> 167fef3d94abc1b400a22c40856cbbf2e635c482
        RECT 24.375 32.900 25.855 32.905 ;
        RECT 25.645 32.410 25.855 32.900 ;
        RECT 26.670 32.410 26.900 32.905 ;
        RECT 25.645 32.210 26.900 32.410 ;
        RECT 26.670 31.905 26.900 32.210 ;
        RECT 26.840 31.500 27.170 31.760 ;
        RECT 37.585 28.600 37.815 33.280 ;
        RECT 38.875 28.920 39.105 33.600 ;
        RECT 40.150 33.280 40.410 33.600 ;
        RECT 38.860 28.600 39.120 28.920 ;
        RECT 40.165 28.600 40.395 33.280 ;
        RECT 41.455 28.920 41.685 33.600 ;
        RECT 42.730 33.280 42.990 33.600 ;
        RECT 44.290 33.360 44.610 33.620 ;
        RECT 41.440 28.600 41.700 28.920 ;
        RECT 42.745 28.600 42.975 33.280 ;
        RECT 44.335 28.650 44.565 33.360 ;
        RECT 37.865 28.410 38.825 28.440 ;
        RECT 39.155 28.410 40.115 28.440 ;
        RECT 40.445 28.410 41.405 28.440 ;
        RECT 41.735 28.410 42.695 28.440 ;
        RECT 37.700 28.240 42.860 28.410 ;
        RECT 44.615 28.260 45.575 28.490 ;
        RECT 37.865 28.210 38.825 28.240 ;
        RECT 39.155 28.210 40.115 28.240 ;
        RECT 40.445 28.210 41.405 28.240 ;
        RECT 41.735 28.210 42.695 28.240 ;
        RECT 37.925 24.720 39.235 26.825 ;
        RECT 46.395 23.270 46.755 23.285 ;
        RECT 46.120 23.040 47.080 23.270 ;
        RECT 46.395 23.025 46.755 23.040 ;
        RECT 18.995 18.720 19.395 18.765 ;
        RECT 18.670 18.490 19.630 18.720 ;
        RECT 18.995 18.465 19.395 18.490 ;
        RECT 18.390 13.265 18.620 18.285 ;
        RECT 45.840 17.885 46.070 22.835 ;
        RECT 45.800 17.625 46.120 17.885 ;
        RECT 45.840 17.535 46.070 17.625 ;
        RECT 63.125 16.755 63.485 16.785 ;
        RECT 62.620 16.725 63.580 16.755 ;
        RECT 63.910 16.725 64.870 16.755 ;
        RECT 65.200 16.725 66.160 16.755 ;
        RECT 66.490 16.725 67.450 16.755 ;
        RECT 67.780 16.725 68.740 16.755 ;
        RECT 69.070 16.725 70.030 16.755 ;
        RECT 70.360 16.725 71.320 16.755 ;
        RECT 71.650 16.725 72.610 16.755 ;
        RECT 72.940 16.725 73.900 16.755 ;
        RECT 74.230 16.725 75.190 16.755 ;
        RECT 75.520 16.725 76.480 16.755 ;
        RECT 76.810 16.725 77.770 16.755 ;
        RECT 78.100 16.725 79.060 16.755 ;
        RECT 79.390 16.725 80.350 16.755 ;
        RECT 80.680 16.725 81.640 16.755 ;
        RECT 62.455 16.555 81.805 16.725 ;
        RECT 62.620 16.525 63.580 16.555 ;
        RECT 63.910 16.525 64.870 16.555 ;
        RECT 65.200 16.525 66.160 16.555 ;
        RECT 66.490 16.525 67.450 16.555 ;
        RECT 67.780 16.525 68.740 16.555 ;
        RECT 69.070 16.525 70.030 16.555 ;
        RECT 70.360 16.525 71.320 16.555 ;
        RECT 71.650 16.525 72.610 16.555 ;
        RECT 72.940 16.525 73.900 16.555 ;
        RECT 74.230 16.525 75.190 16.555 ;
        RECT 75.520 16.525 76.480 16.555 ;
        RECT 76.810 16.525 77.770 16.555 ;
        RECT 78.100 16.525 79.060 16.555 ;
        RECT 79.390 16.525 80.350 16.555 ;
        RECT 80.680 16.525 81.640 16.555 ;
        RECT 63.125 16.520 63.485 16.525 ;
        RECT 46.525 14.335 46.695 14.355 ;
        RECT 45.705 13.395 45.935 14.335 ;
        RECT 46.485 14.285 46.725 14.335 ;
        RECT 46.450 14.025 46.770 14.285 ;
        RECT 18.320 13.000 18.690 13.265 ;
        RECT 45.640 13.135 46.000 13.395 ;
        RECT 45.705 13.085 45.935 13.135 ;
        RECT 46.485 13.100 46.725 14.025 ;
        RECT 47.285 13.395 47.515 14.335 ;
        RECT 47.220 13.135 47.580 13.395 ;
        RECT 18.390 12.985 18.620 13.000 ;
        RECT 46.480 12.625 46.725 13.100 ;
        RECT 47.285 13.085 47.515 13.135 ;
        RECT 45.350 12.395 47.890 12.625 ;
        RECT 18.320 11.540 18.690 11.565 ;
        RECT 16.745 11.300 19.005 11.540 ;
        RECT 44.250 11.420 46.515 11.660 ;
        RECT 46.805 11.420 48.805 11.660 ;
        RECT 16.745 8.955 16.980 11.300 ;
        RECT 44.250 11.185 44.485 11.420 ;
        RECT 48.870 11.260 49.040 11.280 ;
        RECT 48.835 11.185 49.070 11.260 ;
        RECT 19.065 11.140 19.235 11.160 ;
        RECT 19.030 10.330 19.265 11.140 ;
        RECT 44.185 10.925 44.545 11.185 ;
        RECT 48.770 10.925 49.130 11.185 ;
        RECT 44.250 10.610 44.485 10.925 ;
        RECT 48.835 10.610 49.070 10.925 ;
        RECT 62.620 10.785 63.580 10.815 ;
        RECT 63.910 10.785 64.870 10.815 ;
        RECT 65.200 10.785 66.160 10.815 ;
        RECT 66.490 10.785 67.450 10.815 ;
        RECT 67.780 10.785 68.740 10.815 ;
        RECT 69.070 10.785 70.030 10.815 ;
        RECT 70.360 10.785 71.320 10.815 ;
        RECT 71.650 10.785 72.610 10.815 ;
        RECT 72.940 10.785 73.900 10.815 ;
        RECT 74.230 10.785 75.190 10.815 ;
        RECT 75.520 10.785 76.480 10.815 ;
        RECT 76.810 10.785 77.770 10.815 ;
        RECT 78.100 10.785 79.060 10.815 ;
        RECT 79.390 10.785 80.350 10.815 ;
        RECT 80.680 10.785 81.640 10.815 ;
        RECT 62.455 10.615 81.805 10.785 ;
        RECT 62.620 10.585 63.580 10.615 ;
        RECT 63.910 10.585 64.870 10.615 ;
        RECT 65.200 10.585 66.160 10.615 ;
        RECT 66.490 10.585 67.450 10.615 ;
        RECT 67.780 10.585 68.740 10.615 ;
        RECT 69.070 10.585 70.030 10.615 ;
        RECT 70.360 10.585 71.320 10.615 ;
        RECT 71.650 10.585 72.610 10.615 ;
        RECT 72.940 10.585 73.900 10.615 ;
        RECT 74.230 10.585 75.190 10.615 ;
        RECT 75.520 10.585 76.480 10.615 ;
        RECT 76.810 10.585 77.770 10.615 ;
        RECT 78.100 10.585 79.060 10.615 ;
        RECT 79.390 10.585 80.350 10.615 ;
        RECT 80.680 10.585 81.640 10.615 ;
        RECT 19.030 10.090 21.295 10.330 ;
        RECT 48.720 9.330 49.105 9.360 ;
        RECT 42.185 9.300 44.145 9.330 ;
        RECT 44.475 9.300 46.435 9.330 ;
        RECT 46.765 9.300 51.015 9.330 ;
        RECT 51.345 9.300 53.305 9.330 ;
        RECT 53.635 9.300 55.595 9.330 ;
        RECT 55.925 9.300 57.885 9.330 ;
        RECT 58.215 9.300 60.175 9.330 ;
        RECT 60.505 9.300 62.465 9.330 ;
        RECT 62.795 9.300 64.755 9.330 ;
        RECT 65.085 9.300 67.045 9.330 ;
        RECT 67.375 9.300 69.335 9.330 ;
        RECT 69.665 9.300 71.625 9.330 ;
        RECT 71.955 9.300 73.915 9.330 ;
        RECT 74.245 9.300 76.205 9.330 ;
        RECT 76.535 9.300 78.495 9.330 ;
        RECT 78.825 9.300 80.785 9.330 ;
        RECT 81.115 9.300 83.075 9.330 ;
        RECT 83.405 9.300 85.365 9.330 ;
        RECT 85.695 9.300 87.655 9.330 ;
        RECT 87.985 9.300 89.945 9.330 ;
        RECT 90.275 9.300 92.235 9.330 ;
        RECT 92.565 9.300 94.525 9.330 ;
        RECT 94.855 9.300 96.815 9.330 ;
        RECT 97.145 9.300 99.105 9.330 ;
        RECT 99.435 9.300 101.395 9.330 ;
        RECT 101.725 9.300 103.685 9.330 ;
        RECT 104.015 9.300 105.975 9.330 ;
        RECT 106.305 9.300 108.265 9.330 ;
        RECT 108.595 9.300 110.555 9.330 ;
        RECT 42.020 9.130 110.720 9.300 ;
        RECT 42.185 9.100 44.145 9.130 ;
        RECT 44.475 9.100 46.435 9.130 ;
        RECT 46.765 9.100 51.015 9.130 ;
        RECT 51.345 9.100 53.305 9.130 ;
        RECT 53.635 9.100 55.595 9.130 ;
        RECT 55.925 9.100 57.885 9.130 ;
        RECT 58.215 9.100 60.175 9.130 ;
        RECT 60.505 9.100 62.465 9.130 ;
        RECT 62.795 9.100 64.755 9.130 ;
        RECT 65.085 9.100 67.045 9.130 ;
        RECT 67.375 9.100 69.335 9.130 ;
        RECT 69.665 9.100 71.625 9.130 ;
        RECT 71.955 9.100 73.915 9.130 ;
        RECT 74.245 9.100 76.205 9.130 ;
        RECT 76.535 9.100 78.495 9.130 ;
        RECT 78.825 9.100 80.785 9.130 ;
        RECT 81.115 9.100 83.075 9.130 ;
        RECT 83.405 9.100 85.365 9.130 ;
        RECT 85.695 9.100 87.655 9.130 ;
        RECT 87.985 9.100 89.945 9.130 ;
        RECT 90.275 9.100 92.235 9.130 ;
        RECT 92.565 9.100 94.525 9.130 ;
        RECT 94.855 9.100 96.815 9.130 ;
        RECT 97.145 9.100 99.105 9.130 ;
        RECT 99.435 9.100 101.395 9.130 ;
        RECT 101.725 9.100 103.685 9.130 ;
        RECT 104.015 9.100 105.975 9.130 ;
        RECT 106.305 9.100 108.265 9.130 ;
        RECT 108.595 9.100 110.555 9.130 ;
        RECT 16.745 8.715 20.200 8.955 ;
        RECT 17.970 8.555 18.140 8.575 ;
        RECT 17.935 7.905 18.170 8.555 ;
        RECT 42.185 8.100 44.145 8.130 ;
        RECT 44.475 8.100 46.435 8.130 ;
        RECT 46.765 8.100 48.725 8.130 ;
        RECT 49.055 8.100 51.015 8.130 ;
        RECT 51.345 8.100 53.305 8.130 ;
        RECT 53.635 8.100 55.595 8.130 ;
        RECT 55.925 8.100 57.885 8.130 ;
        RECT 58.215 8.100 60.175 8.130 ;
        RECT 60.505 8.100 62.465 8.130 ;
        RECT 62.795 8.100 64.755 8.130 ;
        RECT 65.085 8.100 67.045 8.130 ;
        RECT 67.375 8.100 69.335 8.130 ;
        RECT 69.665 8.100 71.625 8.130 ;
        RECT 71.955 8.100 73.915 8.130 ;
        RECT 74.245 8.100 76.205 8.130 ;
        RECT 76.535 8.100 78.495 8.130 ;
        RECT 78.825 8.100 80.785 8.130 ;
        RECT 81.115 8.100 83.075 8.130 ;
        RECT 83.405 8.100 85.365 8.130 ;
        RECT 85.695 8.100 87.655 8.130 ;
        RECT 87.985 8.100 89.945 8.130 ;
        RECT 90.275 8.100 92.235 8.130 ;
        RECT 92.565 8.100 94.525 8.130 ;
        RECT 94.855 8.100 96.815 8.130 ;
        RECT 97.145 8.100 99.105 8.130 ;
        RECT 99.435 8.100 101.395 8.130 ;
        RECT 101.725 8.100 103.685 8.130 ;
        RECT 104.015 8.100 105.975 8.130 ;
        RECT 106.305 8.100 108.265 8.130 ;
        RECT 108.595 8.100 110.555 8.130 ;
        RECT 42.020 7.930 110.720 8.100 ;
        RECT 42.185 7.900 44.145 7.930 ;
        RECT 44.475 7.900 46.435 7.930 ;
        RECT 46.765 7.900 48.725 7.930 ;
        RECT 49.055 7.900 51.015 7.930 ;
        RECT 51.345 7.900 53.305 7.930 ;
        RECT 53.635 7.900 55.595 7.930 ;
        RECT 55.925 7.900 57.885 7.930 ;
        RECT 58.215 7.900 60.175 7.930 ;
        RECT 60.505 7.900 62.465 7.930 ;
        RECT 62.795 7.900 64.755 7.930 ;
        RECT 65.085 7.900 67.045 7.930 ;
        RECT 67.375 7.900 69.335 7.930 ;
        RECT 69.665 7.900 71.625 7.930 ;
        RECT 71.955 7.900 73.915 7.930 ;
        RECT 74.245 7.900 76.205 7.930 ;
        RECT 76.535 7.900 78.495 7.930 ;
        RECT 78.825 7.900 80.785 7.930 ;
        RECT 81.115 7.900 83.075 7.930 ;
        RECT 83.405 7.900 85.365 7.930 ;
        RECT 85.695 7.900 87.655 7.930 ;
        RECT 87.985 7.900 89.945 7.930 ;
        RECT 90.275 7.900 92.235 7.930 ;
        RECT 92.565 7.900 94.525 7.930 ;
        RECT 94.855 7.900 96.815 7.930 ;
        RECT 97.145 7.900 99.105 7.930 ;
        RECT 99.435 7.900 101.395 7.930 ;
        RECT 101.725 7.900 103.685 7.930 ;
        RECT 104.015 7.900 105.975 7.930 ;
        RECT 106.305 7.900 108.265 7.930 ;
        RECT 108.595 7.900 110.555 7.930 ;
      LAYER met2 ;
        RECT 23.195 33.665 23.465 33.715 ;
        RECT 18.995 33.380 23.465 33.665 ;
        RECT 18.995 32.755 19.400 33.380 ;
        RECT 23.195 33.350 23.465 33.380 ;
        RECT 24.460 33.350 25.730 33.635 ;
        RECT 40.285 33.570 40.545 35.565 ;
        RECT 42.870 34.225 43.130 36.025 ;
        RECT 42.870 34.000 44.580 34.225 ;
        RECT 25.455 33.345 25.730 33.350 ;
        RECT 26.900 33.360 27.160 33.410 ;
        RECT 26.900 33.345 30.690 33.360 ;
        RECT 25.455 33.055 30.690 33.345 ;
        RECT 37.540 33.310 43.020 33.570 ;
        RECT 37.540 33.185 37.795 33.310 ;
        RECT 26.900 33.050 27.160 33.055 ;
        RECT 19.000 31.100 19.400 32.755 ;
        RECT 30.400 32.125 30.690 33.055 ;
        RECT 44.320 32.125 44.580 34.000 ;
        RECT 30.400 31.835 44.580 32.125 ;
        RECT 30.400 31.830 36.565 31.835 ;
        RECT 19.000 30.700 29.545 31.100 ;
        RECT 19.000 18.415 19.400 30.700 ;
        RECT 29.100 23.685 29.545 30.700 ;
        RECT 38.830 28.630 41.730 28.890 ;
        RECT 38.830 26.430 39.150 28.630 ;
        RECT 29.095 23.335 29.550 23.685 ;
        RECT 29.095 23.025 63.760 23.335 ;
        RECT 46.445 22.975 46.705 23.025 ;
        RECT 45.830 16.330 46.090 17.915 ;
        RECT 63.155 16.510 63.475 23.025 ;
        RECT 63.175 16.470 63.435 16.510 ;
        RECT 45.830 16.105 46.740 16.330 ;
        RECT 46.480 13.995 46.740 16.105 ;
        RECT 18.370 11.250 18.640 13.315 ;
        RECT 45.690 12.260 45.950 13.445 ;
        RECT 44.235 12.030 45.950 12.260 ;
        RECT 47.270 12.300 47.530 13.445 ;
        RECT 47.270 12.070 49.080 12.300 ;
        RECT 44.235 10.875 44.495 12.030 ;
        RECT 48.820 11.230 49.080 12.070 ;
        RECT 48.815 9.100 49.080 11.230 ;
        RECT 48.815 9.070 49.075 9.100 ;
  END
END tt_um_analog_ota_version1_IEEE
END LIBRARY

